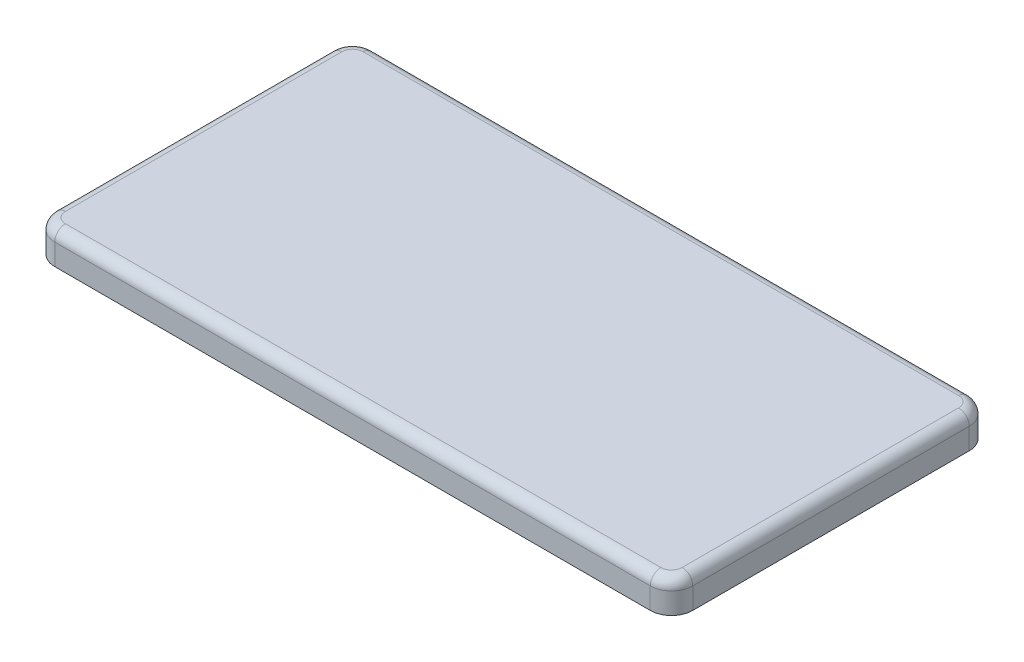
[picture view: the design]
ISO-10303-21;
HEADER;
FILE_DESCRIPTION(('STEP AP214'),'2;1');
FILE_NAME('part.step','',(''),(''),'','','');
FILE_SCHEMA(('AUTOMOTIVE_DESIGN { 1 0 10303 214 1 1 1 1 }'));
ENDSEC;
DATA;
#1=APPLICATION_CONTEXT('core data for automotive mechanical design processes');
#2=APPLICATION_PROTOCOL_DEFINITION('international standard','automotive_design',2000,#1);
#3=PRODUCT_CONTEXT('',#1,'mechanical');
#4=PRODUCT('Part','Part','',(#3));
#5=PRODUCT_RELATED_PRODUCT_CATEGORY('part','',(#4));
#6=PRODUCT_DEFINITION_FORMATION('','',#4);
#7=PRODUCT_DEFINITION_CONTEXT('part definition',#1,'design');
#8=PRODUCT_DEFINITION('design','',#6,#7);
#9=PRODUCT_DEFINITION_SHAPE('','',#8);
#10=(LENGTH_UNIT() NAMED_UNIT(*) SI_UNIT(.MILLI.,.METRE.));
#11=(NAMED_UNIT(*) PLANE_ANGLE_UNIT() SI_UNIT($,.RADIAN.));
#12=(NAMED_UNIT(*) SI_UNIT($,.STERADIAN.) SOLID_ANGLE_UNIT());
#13=UNCERTAINTY_MEASURE_WITH_UNIT(LENGTH_MEASURE(1.E-05),#10,'distance_accuracy_value','');
#14=(GEOMETRIC_REPRESENTATION_CONTEXT(3) GLOBAL_UNCERTAINTY_ASSIGNED_CONTEXT((#13)) GLOBAL_UNIT_ASSIGNED_CONTEXT((#10,
#11,#12)) REPRESENTATION_CONTEXT('',''));
#15=CARTESIAN_POINT('',(0.,0.,0.));
#16=DIRECTION('',(0.,0.,1.));
#17=DIRECTION('',(1.,0.,0.));
#18=AXIS2_PLACEMENT_3D('',#15,#16,#17);
#19=CARTESIAN_POINT('',(-28.,-0.5,13.));
#20=DIRECTION('',(0.,-1.,0.));
#21=DIRECTION('',(0.,0.,-1.));
#22=AXIS2_PLACEMENT_3D('',#19,#20,#21);
#23=PLANE('',#22);
#24=DIRECTION('',(1.,0.,0.));
#25=VECTOR('',#24,1.);
#26=CARTESIAN_POINT('',(-16.65,-0.5,-2.45));
#27=LINE('',#26,#25);
#28=CARTESIAN_POINT('',(-16.65,-0.5,-2.45));
#29=VERTEX_POINT('',#28);
#30=CARTESIAN_POINT('',(-13.35,-0.5,-2.45));
#31=VERTEX_POINT('',#30);
#32=EDGE_CURVE('E282',#29,#31,#27,.T.);
#33=ORIENTED_EDGE('',*,*,#32,.F.);
#34=DIRECTION('',(0.,0.,-1.));
#35=VECTOR('',#34,1.);
#36=CARTESIAN_POINT('',(-16.65,-0.5,2.45));
#37=LINE('',#36,#35);
#38=CARTESIAN_POINT('',(-16.65,-0.5,2.45));
#39=VERTEX_POINT('',#38);
#40=EDGE_CURVE('E256',#39,#29,#37,.T.);
#41=ORIENTED_EDGE('',*,*,#40,.F.);
#42=DIRECTION('',(-1.,0.,0.));
#43=VECTOR('',#42,1.);
#44=CARTESIAN_POINT('',(-16.65,-0.5,2.45));
#45=LINE('',#44,#43);
#46=CARTESIAN_POINT('',(-13.35,-0.5,2.45));
#47=VERTEX_POINT('',#46);
#48=EDGE_CURVE('E288',#47,#39,#45,.T.);
#49=ORIENTED_EDGE('',*,*,#48,.F.);
#50=DIRECTION('',(0.,0.,1.));
#51=VECTOR('',#50,1.);
#52=CARTESIAN_POINT('',(-13.35,-0.5,2.45));
#53=LINE('',#52,#51);
#54=EDGE_CURVE('E285',#31,#47,#53,.T.);
#55=ORIENTED_EDGE('',*,*,#54,.F.);
#56=EDGE_LOOP('',(#33,#41,#49,#55));
#57=FACE_BOUND('',#56,.T.);
#58=CARTESIAN_POINT('',(-28.,-0.5,13.));
#59=DIRECTION('',(0.,-1.,0.));
#60=DIRECTION('',(0.,0.,-1.));
#61=AXIS2_PLACEMENT_3D('',#58,#59,#60);
#62=CIRCLE('',#61,0.2);
#63=CARTESIAN_POINT('',(-28.,-0.5,13.2));
#64=VERTEX_POINT('',#63);
#65=CARTESIAN_POINT('',(-28.2,-0.5,13.));
#66=VERTEX_POINT('',#65);
#67=EDGE_CURVE('E300',#64,#66,#62,.T.);
#68=ORIENTED_EDGE('',*,*,#67,.T.);
#69=DIRECTION('',(0.,0.,-1.));
#70=VECTOR('',#69,1.);
#71=CARTESIAN_POINT('',(-28.2,-0.5,13.));
#72=LINE('',#71,#70);
#73=CARTESIAN_POINT('',(-28.2,-0.5,-13.));
#74=VERTEX_POINT('',#73);
#75=EDGE_CURVE('E303',#66,#74,#72,.T.);
#76=ORIENTED_EDGE('',*,*,#75,.T.);
#77=CARTESIAN_POINT('',(-28.,-0.5,-13.));
#78=DIRECTION('',(0.,-1.,0.));
#79=DIRECTION('',(0.,0.,-1.));
#80=AXIS2_PLACEMENT_3D('',#77,#78,#79);
#81=CIRCLE('',#80,0.2);
#82=CARTESIAN_POINT('',(-28.,-0.5,-13.2));
#83=VERTEX_POINT('',#82);
#84=EDGE_CURVE('E307',#74,#83,#81,.T.);
#85=ORIENTED_EDGE('',*,*,#84,.T.);
#86=DIRECTION('',(1.,0.,0.));
#87=VECTOR('',#86,1.);
#88=CARTESIAN_POINT('',(-28.,-0.5,-13.2));
#89=LINE('',#88,#87);
#90=CARTESIAN_POINT('',(28.,-0.5,-13.2));
#91=VERTEX_POINT('',#90);
#92=EDGE_CURVE('E310',#83,#91,#89,.T.);
#93=ORIENTED_EDGE('',*,*,#92,.T.);
#94=CARTESIAN_POINT('',(28.,-0.5,-13.));
#95=DIRECTION('',(0.,-1.,0.));
#96=DIRECTION('',(0.,0.,-1.));
#97=AXIS2_PLACEMENT_3D('',#94,#95,#96);
#98=CIRCLE('',#97,0.200000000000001);
#99=CARTESIAN_POINT('',(28.2,-0.5,-13.));
#100=VERTEX_POINT('',#99);
#101=EDGE_CURVE('E313',#91,#100,#98,.T.);
#102=ORIENTED_EDGE('',*,*,#101,.T.);
#103=DIRECTION('',(0.,0.,1.));
#104=VECTOR('',#103,1.);
#105=CARTESIAN_POINT('',(28.2,-0.5,13.));
#106=LINE('',#105,#104);
#107=CARTESIAN_POINT('',(28.2,-0.5,13.));
#108=VERTEX_POINT('',#107);
#109=EDGE_CURVE('E316',#100,#108,#106,.T.);
#110=ORIENTED_EDGE('',*,*,#109,.T.);
#111=CARTESIAN_POINT('',(28.,-0.5,13.));
#112=DIRECTION('',(0.,-1.,0.));
#113=DIRECTION('',(0.,0.,-1.));
#114=AXIS2_PLACEMENT_3D('',#111,#112,#113);
#115=CIRCLE('',#114,0.199999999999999);
#116=CARTESIAN_POINT('',(28.,-0.5,13.2));
#117=VERTEX_POINT('',#116);
#118=EDGE_CURVE('E319',#108,#117,#115,.T.);
#119=ORIENTED_EDGE('',*,*,#118,.T.);
#120=DIRECTION('',(-1.,0.,0.));
#121=VECTOR('',#120,1.);
#122=CARTESIAN_POINT('',(-28.,-0.5,13.2));
#123=LINE('',#122,#121);
#124=EDGE_CURVE('E322',#117,#64,#123,.T.);
#125=ORIENTED_EDGE('',*,*,#124,.T.);
#126=EDGE_LOOP('',(#68,#76,#85,#93,#102,#110,#119,#125));
#127=FACE_BOUND('',#126,.T.);
#128=DIRECTION('',(1.,0.,0.));
#129=VECTOR('',#128,1.);
#130=CARTESIAN_POINT('',(13.35,-0.5,-2.45));
#131=LINE('',#130,#129);
#132=CARTESIAN_POINT('',(13.35,-0.5,-2.45));
#133=VERTEX_POINT('',#132);
#134=CARTESIAN_POINT('',(16.65,-0.5,-2.45));
#135=VERTEX_POINT('',#134);
#136=EDGE_CURVE('E250',#133,#135,#131,.T.);
#137=ORIENTED_EDGE('',*,*,#136,.F.);
#138=DIRECTION('',(0.,0.,-1.));
#139=VECTOR('',#138,1.);
#140=CARTESIAN_POINT('',(13.35,-0.5,-2.45));
#141=LINE('',#140,#139);
#142=CARTESIAN_POINT('',(13.35,-0.5,2.45));
#143=VERTEX_POINT('',#142);
#144=EDGE_CURVE('E260',#143,#133,#141,.T.);
#145=ORIENTED_EDGE('',*,*,#144,.F.);
#146=DIRECTION('',(-1.,0.,0.));
#147=VECTOR('',#146,1.);
#148=CARTESIAN_POINT('',(13.35,-0.5,2.45));
#149=LINE('',#148,#147);
#150=CARTESIAN_POINT('',(16.65,-0.5,2.45));
#151=VERTEX_POINT('',#150);
#152=EDGE_CURVE('E272',#151,#143,#149,.T.);
#153=ORIENTED_EDGE('',*,*,#152,.F.);
#154=DIRECTION('',(0.,0.,1.));
#155=VECTOR('',#154,1.);
#156=CARTESIAN_POINT('',(16.65,-0.5,-2.45));
#157=LINE('',#156,#155);
#158=EDGE_CURVE('E270',#135,#151,#157,.T.);
#159=ORIENTED_EDGE('',*,*,#158,.F.);
#160=EDGE_LOOP('',(#137,#145,#153,#159));
#161=FACE_BOUND('',#160,.T.);
#162=ADVANCED_FACE('F35',(#57,#127,#161),#23,.T.);
#163=CARTESIAN_POINT('',(-28.,1.5,-13.));
#164=DIRECTION('',(0.,-1.,0.));
#165=DIRECTION('',(0.,0.,-1.));
#166=AXIS2_PLACEMENT_3D('',#163,#164,#165);
#167=CYLINDRICAL_SURFACE('',#166,2.);
#168=DIRECTION('',(0.,-1.,0.));
#169=VECTOR('',#168,1.);
#170=CARTESIAN_POINT('',(-30.,1.5,-13.));
#171=LINE('',#170,#169);
#172=CARTESIAN_POINT('',(-30.,0.5,-13.));
#173=VERTEX_POINT('',#172);
#174=CARTESIAN_POINT('',(-30.,-1.5,-13.));
#175=VERTEX_POINT('',#174);
#176=EDGE_CURVE('E403',#173,#175,#171,.T.);
#177=ORIENTED_EDGE('',*,*,#176,.F.);
#178=CARTESIAN_POINT('',(-28.,0.5,-13.));
#179=DIRECTION('',(0.,1.,0.));
#180=DIRECTION('',(0.,0.,1.));
#181=AXIS2_PLACEMENT_3D('',#178,#179,#180);
#182=CIRCLE('',#181,2.);
#183=CARTESIAN_POINT('',(-28.,0.5,-15.));
#184=VERTEX_POINT('',#183);
#185=EDGE_CURVE('E427',#173,#184,#182,.F.);
#186=ORIENTED_EDGE('',*,*,#185,.T.);
#187=DIRECTION('',(0.,-1.,0.));
#188=VECTOR('',#187,1.);
#189=CARTESIAN_POINT('',(-28.,1.5,-15.));
#190=LINE('',#189,#188);
#191=CARTESIAN_POINT('',(-28.,-1.5,-15.));
#192=VERTEX_POINT('',#191);
#193=EDGE_CURVE('E389',#184,#192,#190,.T.);
#194=ORIENTED_EDGE('',*,*,#193,.T.);
#195=CARTESIAN_POINT('',(-28.,-1.5,-13.));
#196=DIRECTION('',(0.,1.,0.));
#197=DIRECTION('',(0.,0.,1.));
#198=AXIS2_PLACEMENT_3D('',#195,#196,#197);
#199=CIRCLE('',#198,2.);
#200=EDGE_CURVE('E364',#192,#175,#199,.T.);
#201=ORIENTED_EDGE('',*,*,#200,.T.);
#202=EDGE_LOOP('',(#177,#186,#194,#201));
#203=FACE_BOUND('',#202,.T.);
#204=ADVANCED_FACE('F543',(#203),#167,.T.);
#205=CARTESIAN_POINT('',(-30.,1.5,13.));
#206=DIRECTION('',(1.,0.,0.));
#207=DIRECTION('',(0.,0.,-1.));
#208=AXIS2_PLACEMENT_3D('',#205,#206,#207);
#209=PLANE('',#208);
#210=DIRECTION('',(0.,-1.,0.));
#211=VECTOR('',#210,1.);
#212=CARTESIAN_POINT('',(-30.,1.5,13.));
#213=LINE('',#212,#211);
#214=CARTESIAN_POINT('',(-30.,0.5,13.));
#215=VERTEX_POINT('',#214);
#216=CARTESIAN_POINT('',(-30.,-1.5,13.));
#217=VERTEX_POINT('',#216);
#218=EDGE_CURVE('E401',#215,#217,#213,.T.);
#219=ORIENTED_EDGE('',*,*,#218,.F.);
#220=DIRECTION('',(0.,0.,1.));
#221=VECTOR('',#220,1.);
#222=CARTESIAN_POINT('',(-30.,0.5,-13.));
#223=LINE('',#222,#221);
#224=EDGE_CURVE('E425',#215,#173,#223,.F.);
#225=ORIENTED_EDGE('',*,*,#224,.T.);
#226=ORIENTED_EDGE('',*,*,#176,.T.);
#227=DIRECTION('',(0.,0.,1.));
#228=VECTOR('',#227,1.);
#229=CARTESIAN_POINT('',(-30.,-1.5,13.));
#230=LINE('',#229,#228);
#231=EDGE_CURVE('E367',#175,#217,#230,.T.);
#232=ORIENTED_EDGE('',*,*,#231,.T.);
#233=EDGE_LOOP('',(#219,#225,#226,#232));
#234=FACE_BOUND('',#233,.T.);
#235=ADVANCED_FACE('F549',(#234),#209,.F.);
#236=CARTESIAN_POINT('',(-28.,1.5,13.));
#237=DIRECTION('',(0.,-1.,0.));
#238=DIRECTION('',(0.,0.,-1.));
#239=AXIS2_PLACEMENT_3D('',#236,#237,#238);
#240=CYLINDRICAL_SURFACE('',#239,2.);
#241=DIRECTION('',(0.,-1.,0.));
#242=VECTOR('',#241,1.);
#243=CARTESIAN_POINT('',(-28.,1.5,15.));
#244=LINE('',#243,#242);
#245=CARTESIAN_POINT('',(-28.,0.5,15.));
#246=VERTEX_POINT('',#245);
#247=CARTESIAN_POINT('',(-28.,-1.5,15.));
#248=VERTEX_POINT('',#247);
#249=EDGE_CURVE('E399',#246,#248,#244,.T.);
#250=ORIENTED_EDGE('',*,*,#249,.F.);
#251=CARTESIAN_POINT('',(-28.,0.5,13.));
#252=DIRECTION('',(0.,1.,0.));
#253=DIRECTION('',(0.,0.,1.));
#254=AXIS2_PLACEMENT_3D('',#251,#252,#253);
#255=CIRCLE('',#254,2.);
#256=EDGE_CURVE('E422',#246,#215,#255,.F.);
#257=ORIENTED_EDGE('',*,*,#256,.T.);
#258=ORIENTED_EDGE('',*,*,#218,.T.);
#259=CARTESIAN_POINT('',(-28.,-1.5,13.));
#260=DIRECTION('',(0.,1.,0.));
#261=DIRECTION('',(0.,0.,1.));
#262=AXIS2_PLACEMENT_3D('',#259,#260,#261);
#263=CIRCLE('',#262,2.);
#264=EDGE_CURVE('E371',#217,#248,#263,.T.);
#265=ORIENTED_EDGE('',*,*,#264,.T.);
#266=EDGE_LOOP('',(#250,#257,#258,#265));
#267=FACE_BOUND('',#266,.T.);
#268=ADVANCED_FACE('F619',(#267),#240,.T.);
#269=CARTESIAN_POINT('',(-28.,1.5,15.));
#270=DIRECTION('',(0.,0.,-1.));
#271=DIRECTION('',(-1.,0.,0.));
#272=AXIS2_PLACEMENT_3D('',#269,#270,#271);
#273=PLANE('',#272);
#274=DIRECTION('',(0.,-1.,0.));
#275=VECTOR('',#274,1.);
#276=CARTESIAN_POINT('',(28.,1.5,15.));
#277=LINE('',#276,#275);
#278=CARTESIAN_POINT('',(28.,0.5,15.));
#279=VERTEX_POINT('',#278);
#280=CARTESIAN_POINT('',(28.,-1.5,15.));
#281=VERTEX_POINT('',#280);
#282=EDGE_CURVE('E397',#279,#281,#277,.T.);
#283=ORIENTED_EDGE('',*,*,#282,.F.);
#284=DIRECTION('',(1.,0.,0.));
#285=VECTOR('',#284,1.);
#286=CARTESIAN_POINT('',(-28.,0.5,15.));
#287=LINE('',#286,#285);
#288=EDGE_CURVE('E437',#279,#246,#287,.F.);
#289=ORIENTED_EDGE('',*,*,#288,.T.);
#290=ORIENTED_EDGE('',*,*,#249,.T.);
#291=DIRECTION('',(1.,0.,0.));
#292=VECTOR('',#291,1.);
#293=CARTESIAN_POINT('',(-28.,-1.5,15.));
#294=LINE('',#293,#292);
#295=EDGE_CURVE('E374',#248,#281,#294,.T.);
#296=ORIENTED_EDGE('',*,*,#295,.T.);
#297=EDGE_LOOP('',(#283,#289,#290,#296));
#298=FACE_BOUND('',#297,.T.);
#299=ADVANCED_FACE('F615',(#298),#273,.F.);
#300=CARTESIAN_POINT('',(28.,1.5,13.));
#301=DIRECTION('',(0.,-1.,0.));
#302=DIRECTION('',(0.,0.,-1.));
#303=AXIS2_PLACEMENT_3D('',#300,#301,#302);
#304=CYLINDRICAL_SURFACE('',#303,2.);
#305=DIRECTION('',(0.,-1.,0.));
#306=VECTOR('',#305,1.);
#307=CARTESIAN_POINT('',(30.,1.5,13.));
#308=LINE('',#307,#306);
#309=CARTESIAN_POINT('',(30.,0.5,13.));
#310=VERTEX_POINT('',#309);
#311=CARTESIAN_POINT('',(30.,-1.5,13.));
#312=VERTEX_POINT('',#311);
#313=EDGE_CURVE('E395',#310,#312,#308,.T.);
#314=ORIENTED_EDGE('',*,*,#313,.F.);
#315=CARTESIAN_POINT('',(28.,0.5,13.));
#316=DIRECTION('',(0.,1.,0.));
#317=DIRECTION('',(0.,0.,1.));
#318=AXIS2_PLACEMENT_3D('',#315,#316,#317);
#319=CIRCLE('',#318,2.);
#320=EDGE_CURVE('E435',#310,#279,#319,.F.);
#321=ORIENTED_EDGE('',*,*,#320,.T.);
#322=ORIENTED_EDGE('',*,*,#282,.T.);
#323=CARTESIAN_POINT('',(28.,-1.5,13.));
#324=DIRECTION('',(0.,1.,0.));
#325=DIRECTION('',(0.,0.,1.));
#326=AXIS2_PLACEMENT_3D('',#323,#324,#325);
#327=CIRCLE('',#326,2.);
#328=EDGE_CURVE('E377',#281,#312,#327,.T.);
#329=ORIENTED_EDGE('',*,*,#328,.T.);
#330=EDGE_LOOP('',(#314,#321,#322,#329));
#331=FACE_BOUND('',#330,.T.);
#332=ADVANCED_FACE('F611',(#331),#304,.T.);
#333=CARTESIAN_POINT('',(30.,1.5,13.));
#334=DIRECTION('',(-1.,0.,0.));
#335=DIRECTION('',(0.,0.,1.));
#336=AXIS2_PLACEMENT_3D('',#333,#334,#335);
#337=PLANE('',#336);
#338=DIRECTION('',(0.,-1.,0.));
#339=VECTOR('',#338,1.);
#340=CARTESIAN_POINT('',(30.,1.5,-13.));
#341=LINE('',#340,#339);
#342=CARTESIAN_POINT('',(30.,0.5,-13.));
#343=VERTEX_POINT('',#342);
#344=CARTESIAN_POINT('',(30.,-1.5,-13.));
#345=VERTEX_POINT('',#344);
#346=EDGE_CURVE('E393',#343,#345,#341,.T.);
#347=ORIENTED_EDGE('',*,*,#346,.F.);
#348=DIRECTION('',(0.,0.,-1.));
#349=VECTOR('',#348,1.);
#350=CARTESIAN_POINT('',(30.,0.5,13.));
#351=LINE('',#350,#349);
#352=EDGE_CURVE('E433',#343,#310,#351,.F.);
#353=ORIENTED_EDGE('',*,*,#352,.T.);
#354=ORIENTED_EDGE('',*,*,#313,.T.);
#355=DIRECTION('',(0.,0.,-1.));
#356=VECTOR('',#355,1.);
#357=CARTESIAN_POINT('',(30.,-1.5,13.));
#358=LINE('',#357,#356);
#359=EDGE_CURVE('E380',#312,#345,#358,.T.);
#360=ORIENTED_EDGE('',*,*,#359,.T.);
#361=EDGE_LOOP('',(#347,#353,#354,#360));
#362=FACE_BOUND('',#361,.T.);
#363=ADVANCED_FACE('F607',(#362),#337,.F.);
#364=CARTESIAN_POINT('',(28.,1.5,-13.));
#365=DIRECTION('',(0.,-1.,0.));
#366=DIRECTION('',(0.,0.,-1.));
#367=AXIS2_PLACEMENT_3D('',#364,#365,#366);
#368=CYLINDRICAL_SURFACE('',#367,2.);
#369=DIRECTION('',(0.,-1.,0.));
#370=VECTOR('',#369,1.);
#371=CARTESIAN_POINT('',(28.,1.5,-15.));
#372=LINE('',#371,#370);
#373=CARTESIAN_POINT('',(28.,0.5,-15.));
#374=VERTEX_POINT('',#373);
#375=CARTESIAN_POINT('',(28.,-1.5,-15.));
#376=VERTEX_POINT('',#375);
#377=EDGE_CURVE('E391',#374,#376,#372,.T.);
#378=ORIENTED_EDGE('',*,*,#377,.F.);
#379=CARTESIAN_POINT('',(28.,0.5,-13.));
#380=DIRECTION('',(0.,1.,0.));
#381=DIRECTION('',(0.,0.,1.));
#382=AXIS2_PLACEMENT_3D('',#379,#380,#381);
#383=CIRCLE('',#382,2.);
#384=EDGE_CURVE('E431',#374,#343,#383,.F.);
#385=ORIENTED_EDGE('',*,*,#384,.T.);
#386=ORIENTED_EDGE('',*,*,#346,.T.);
#387=CARTESIAN_POINT('',(28.,-1.5,-13.));
#388=DIRECTION('',(0.,1.,0.));
#389=DIRECTION('',(0.,0.,1.));
#390=AXIS2_PLACEMENT_3D('',#387,#388,#389);
#391=CIRCLE('',#390,2.);
#392=EDGE_CURVE('E383',#345,#376,#391,.T.);
#393=ORIENTED_EDGE('',*,*,#392,.T.);
#394=EDGE_LOOP('',(#378,#385,#386,#393));
#395=FACE_BOUND('',#394,.T.);
#396=ADVANCED_FACE('F603',(#395),#368,.T.);
#397=CARTESIAN_POINT('',(-28.,1.5,-15.));
#398=DIRECTION('',(0.,0.,1.));
#399=DIRECTION('',(1.,0.,0.));
#400=AXIS2_PLACEMENT_3D('',#397,#398,#399);
#401=PLANE('',#400);
#402=ORIENTED_EDGE('',*,*,#193,.F.);
#403=DIRECTION('',(-1.,0.,0.));
#404=VECTOR('',#403,1.);
#405=CARTESIAN_POINT('',(28.,0.5,-15.));
#406=LINE('',#405,#404);
#407=EDGE_CURVE('E429',#184,#374,#406,.F.);
#408=ORIENTED_EDGE('',*,*,#407,.T.);
#409=ORIENTED_EDGE('',*,*,#377,.T.);
#410=DIRECTION('',(-1.,0.,0.));
#411=VECTOR('',#410,1.);
#412=CARTESIAN_POINT('',(-28.,-1.5,-15.));
#413=LINE('',#412,#411);
#414=EDGE_CURVE('E386',#376,#192,#413,.T.);
#415=ORIENTED_EDGE('',*,*,#414,.T.);
#416=EDGE_LOOP('',(#402,#408,#409,#415));
#417=FACE_BOUND('',#416,.T.);
#418=ADVANCED_FACE('F595',(#417),#401,.F.);
#419=CARTESIAN_POINT('',(-28.,1.5,-13.));
#420=DIRECTION('',(0.,1.,0.));
#421=DIRECTION('',(0.,0.,1.));
#422=AXIS2_PLACEMENT_3D('',#419,#420,#421);
#423=PLANE('',#422);
#424=DIRECTION('',(0.,0.,1.));
#425=VECTOR('',#424,1.);
#426=CARTESIAN_POINT('',(-29.,1.5,13.));
#427=LINE('',#426,#425);
#428=CARTESIAN_POINT('',(-29.,1.5,-13.));
#429=VERTEX_POINT('',#428);
#430=CARTESIAN_POINT('',(-29.,1.5,13.));
#431=VERTEX_POINT('',#430);
#432=EDGE_CURVE('E417',#429,#431,#427,.T.);
#433=ORIENTED_EDGE('',*,*,#432,.T.);
#434=CARTESIAN_POINT('',(-28.,1.5,13.));
#435=DIRECTION('',(0.,1.,0.));
#436=DIRECTION('',(0.,0.,1.));
#437=AXIS2_PLACEMENT_3D('',#434,#435,#436);
#438=CIRCLE('',#437,1.);
#439=CARTESIAN_POINT('',(-28.,1.5,14.));
#440=VERTEX_POINT('',#439);
#441=EDGE_CURVE('E419',#431,#440,#438,.T.);
#442=ORIENTED_EDGE('',*,*,#441,.T.);
#443=DIRECTION('',(1.,0.,0.));
#444=VECTOR('',#443,1.);
#445=CARTESIAN_POINT('',(28.,1.5,14.));
#446=LINE('',#445,#444);
#447=CARTESIAN_POINT('',(28.,1.5,14.));
#448=VERTEX_POINT('',#447);
#449=EDGE_CURVE('E405',#440,#448,#446,.T.);
#450=ORIENTED_EDGE('',*,*,#449,.T.);
#451=CARTESIAN_POINT('',(28.,1.5,13.));
#452=DIRECTION('',(0.,1.,0.));
#453=DIRECTION('',(0.,0.,1.));
#454=AXIS2_PLACEMENT_3D('',#451,#452,#453);
#455=CIRCLE('',#454,1.);
#456=CARTESIAN_POINT('',(29.,1.5,13.));
#457=VERTEX_POINT('',#456);
#458=EDGE_CURVE('E407',#448,#457,#455,.T.);
#459=ORIENTED_EDGE('',*,*,#458,.T.);
#460=DIRECTION('',(0.,0.,-1.));
#461=VECTOR('',#460,1.);
#462=CARTESIAN_POINT('',(29.,1.5,-13.));
#463=LINE('',#462,#461);
#464=CARTESIAN_POINT('',(29.,1.5,-13.));
#465=VERTEX_POINT('',#464);
#466=EDGE_CURVE('E409',#457,#465,#463,.T.);
#467=ORIENTED_EDGE('',*,*,#466,.T.);
#468=CARTESIAN_POINT('',(28.,1.5,-13.));
#469=DIRECTION('',(0.,1.,0.));
#470=DIRECTION('',(0.,0.,1.));
#471=AXIS2_PLACEMENT_3D('',#468,#469,#470);
#472=CIRCLE('',#471,1.);
#473=CARTESIAN_POINT('',(28.,1.5,-14.));
#474=VERTEX_POINT('',#473);
#475=EDGE_CURVE('E411',#465,#474,#472,.T.);
#476=ORIENTED_EDGE('',*,*,#475,.T.);
#477=DIRECTION('',(-1.,0.,0.));
#478=VECTOR('',#477,1.);
#479=CARTESIAN_POINT('',(-28.,1.5,-14.));
#480=LINE('',#479,#478);
#481=CARTESIAN_POINT('',(-28.,1.5,-14.));
#482=VERTEX_POINT('',#481);
#483=EDGE_CURVE('E413',#474,#482,#480,.T.);
#484=ORIENTED_EDGE('',*,*,#483,.T.);
#485=CARTESIAN_POINT('',(-28.,1.5,-13.));
#486=DIRECTION('',(0.,1.,0.));
#487=DIRECTION('',(0.,0.,1.));
#488=AXIS2_PLACEMENT_3D('',#485,#486,#487);
#489=CIRCLE('',#488,1.);
#490=EDGE_CURVE('E415',#482,#429,#489,.T.);
#491=ORIENTED_EDGE('',*,*,#490,.T.);
#492=EDGE_LOOP('',(#433,#442,#450,#459,#467,#476,#484,#491));
#493=FACE_BOUND('',#492,.T.);
#494=ADVANCED_FACE('F591',(#493),#423,.T.);
#495=CARTESIAN_POINT('',(-28.,-1.5,-13.));
#496=DIRECTION('',(0.,1.,0.));
#497=DIRECTION('',(0.,0.,1.));
#498=AXIS2_PLACEMENT_3D('',#495,#496,#497);
#499=PLANE('',#498);
#500=DIRECTION('',(0.,0.,-1.));
#501=VECTOR('',#500,1.);
#502=CARTESIAN_POINT('',(-28.2,-1.5,13.));
#503=LINE('',#502,#501);
#504=CARTESIAN_POINT('',(-28.2,-1.5,13.));
#505=VERTEX_POINT('',#504);
#506=CARTESIAN_POINT('',(-28.2,-1.5,-13.));
#507=VERTEX_POINT('',#506);
#508=EDGE_CURVE('E327',#505,#507,#503,.T.);
#509=ORIENTED_EDGE('',*,*,#508,.F.);
#510=CARTESIAN_POINT('',(-28.,-1.5,13.));
#511=DIRECTION('',(0.,-1.,0.));
#512=DIRECTION('',(0.,0.,-1.));
#513=AXIS2_PLACEMENT_3D('',#510,#511,#512);
#514=CIRCLE('',#513,0.2);
#515=CARTESIAN_POINT('',(-28.,-1.5,13.2));
#516=VERTEX_POINT('',#515);
#517=EDGE_CURVE('E294',#516,#505,#514,.T.);
#518=ORIENTED_EDGE('',*,*,#517,.F.);
#519=DIRECTION('',(-1.,0.,0.));
#520=VECTOR('',#519,1.);
#521=CARTESIAN_POINT('',(-28.,-1.5,13.2));
#522=LINE('',#521,#520);
#523=CARTESIAN_POINT('',(28.,-1.5,13.2));
#524=VERTEX_POINT('',#523);
#525=EDGE_CURVE('E304',#524,#516,#522,.T.);
#526=ORIENTED_EDGE('',*,*,#525,.F.);
#527=CARTESIAN_POINT('',(28.,-1.5,13.));
#528=DIRECTION('',(0.,-1.,0.));
#529=DIRECTION('',(0.,0.,-1.));
#530=AXIS2_PLACEMENT_3D('',#527,#528,#529);
#531=CIRCLE('',#530,0.199999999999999);
#532=CARTESIAN_POINT('',(28.2,-1.5,13.));
#533=VERTEX_POINT('',#532);
#534=EDGE_CURVE('E342',#533,#524,#531,.T.);
#535=ORIENTED_EDGE('',*,*,#534,.F.);
#536=DIRECTION('',(0.,0.,1.));
#537=VECTOR('',#536,1.);
#538=CARTESIAN_POINT('',(28.2,-1.5,13.));
#539=LINE('',#538,#537);
#540=CARTESIAN_POINT('',(28.2,-1.5,-13.));
#541=VERTEX_POINT('',#540);
#542=EDGE_CURVE('E339',#541,#533,#539,.T.);
#543=ORIENTED_EDGE('',*,*,#542,.F.);
#544=CARTESIAN_POINT('',(28.,-1.5,-13.));
#545=DIRECTION('',(0.,-1.,0.));
#546=DIRECTION('',(0.,0.,-1.));
#547=AXIS2_PLACEMENT_3D('',#544,#545,#546);
#548=CIRCLE('',#547,0.200000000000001);
#549=CARTESIAN_POINT('',(28.,-1.5,-13.2));
#550=VERTEX_POINT('',#549);
#551=EDGE_CURVE('E336',#550,#541,#548,.T.);
#552=ORIENTED_EDGE('',*,*,#551,.F.);
#553=DIRECTION('',(1.,0.,0.));
#554=VECTOR('',#553,1.);
#555=CARTESIAN_POINT('',(-28.,-1.5,-13.2));
#556=LINE('',#555,#554);
#557=CARTESIAN_POINT('',(-28.,-1.5,-13.2));
#558=VERTEX_POINT('',#557);
#559=EDGE_CURVE('E333',#558,#550,#556,.T.);
#560=ORIENTED_EDGE('',*,*,#559,.F.);
#561=CARTESIAN_POINT('',(-28.,-1.5,-13.));
#562=DIRECTION('',(0.,-1.,0.));
#563=DIRECTION('',(0.,0.,-1.));
#564=AXIS2_PLACEMENT_3D('',#561,#562,#563);
#565=CIRCLE('',#564,0.2);
#566=EDGE_CURVE('E330',#507,#558,#565,.T.);
#567=ORIENTED_EDGE('',*,*,#566,.F.);
#568=EDGE_LOOP('',(#509,#518,#526,#535,#543,#552,#560,#567));
#569=FACE_BOUND('',#568,.T.);
#570=ORIENTED_EDGE('',*,*,#200,.F.);
#571=ORIENTED_EDGE('',*,*,#414,.F.);
#572=ORIENTED_EDGE('',*,*,#392,.F.);
#573=ORIENTED_EDGE('',*,*,#359,.F.);
#574=ORIENTED_EDGE('',*,*,#328,.F.);
#575=ORIENTED_EDGE('',*,*,#295,.F.);
#576=ORIENTED_EDGE('',*,*,#264,.F.);
#577=ORIENTED_EDGE('',*,*,#231,.F.);
#578=EDGE_LOOP('',(#570,#571,#572,#573,#574,#575,#576,#577));
#579=FACE_BOUND('',#578,.T.);
#580=ADVANCED_FACE('F594',(#569,#579),#499,.F.);
#581=CARTESIAN_POINT('',(28.,0.5,-13.));
#582=DIRECTION('',(0.,1.,0.));
#583=DIRECTION('',(0.,0.,1.));
#584=AXIS2_PLACEMENT_3D('',#581,#582,#583);
#585=TOROIDAL_SURFACE('',#584,1.,1.);
#586=CARTESIAN_POINT('',(29.,0.5,-13.));
#587=DIRECTION('',(0.,0.,1.));
#588=DIRECTION('',(1.,0.,0.));
#589=AXIS2_PLACEMENT_3D('',#586,#587,#588);
#590=CIRCLE('',#589,1.);
#591=EDGE_CURVE('E455',#343,#465,#590,.T.);
#592=ORIENTED_EDGE('',*,*,#591,.F.);
#593=ORIENTED_EDGE('',*,*,#384,.F.);
#594=CARTESIAN_POINT('',(28.,0.5,-14.));
#595=DIRECTION('',(-1.,0.,0.));
#596=DIRECTION('',(0.,0.,1.));
#597=AXIS2_PLACEMENT_3D('',#594,#595,#596);
#598=CIRCLE('',#597,1.);
#599=EDGE_CURVE('E368',#474,#374,#598,.T.);
#600=ORIENTED_EDGE('',*,*,#599,.F.);
#601=ORIENTED_EDGE('',*,*,#475,.F.);
#602=EDGE_LOOP('',(#592,#593,#600,#601));
#603=FACE_BOUND('',#602,.T.);
#604=ADVANCED_FACE('F599',(#603),#585,.T.);
#605=CARTESIAN_POINT('',(-28.,0.5,-14.));
#606=DIRECTION('',(1.,0.,0.));
#607=DIRECTION('',(0.,0.,-1.));
#608=AXIS2_PLACEMENT_3D('',#605,#606,#607);
#609=CYLINDRICAL_SURFACE('',#608,1.);
#610=ORIENTED_EDGE('',*,*,#599,.T.);
#611=ORIENTED_EDGE('',*,*,#407,.F.);
#612=CARTESIAN_POINT('',(-28.,0.5,-14.));
#613=DIRECTION('',(-1.,0.,0.));
#614=DIRECTION('',(0.,0.,1.));
#615=AXIS2_PLACEMENT_3D('',#612,#613,#614);
#616=CIRCLE('',#615,1.);
#617=EDGE_CURVE('E452',#482,#184,#616,.T.);
#618=ORIENTED_EDGE('',*,*,#617,.F.);
#619=ORIENTED_EDGE('',*,*,#483,.F.);
#620=EDGE_LOOP('',(#610,#611,#618,#619));
#621=FACE_BOUND('',#620,.T.);
#622=ADVANCED_FACE('F649',(#621),#609,.T.);
#623=CARTESIAN_POINT('',(29.,0.5,-13.));
#624=DIRECTION('',(0.,0.,1.));
#625=DIRECTION('',(1.,0.,0.));
#626=AXIS2_PLACEMENT_3D('',#623,#624,#625);
#627=CYLINDRICAL_SURFACE('',#626,1.);
#628=ORIENTED_EDGE('',*,*,#591,.T.);
#629=ORIENTED_EDGE('',*,*,#466,.F.);
#630=CARTESIAN_POINT('',(29.,0.5,13.));
#631=DIRECTION('',(0.,0.,1.));
#632=DIRECTION('',(1.,0.,0.));
#633=AXIS2_PLACEMENT_3D('',#630,#631,#632);
#634=CIRCLE('',#633,1.);
#635=EDGE_CURVE('E449',#310,#457,#634,.T.);
#636=ORIENTED_EDGE('',*,*,#635,.F.);
#637=ORIENTED_EDGE('',*,*,#352,.F.);
#638=EDGE_LOOP('',(#628,#629,#636,#637));
#639=FACE_BOUND('',#638,.T.);
#640=ADVANCED_FACE('F645',(#639),#627,.T.);
#641=CARTESIAN_POINT('',(-28.,0.5,-13.));
#642=DIRECTION('',(0.,1.,0.));
#643=DIRECTION('',(0.,0.,1.));
#644=AXIS2_PLACEMENT_3D('',#641,#642,#643);
#645=TOROIDAL_SURFACE('',#644,1.,1.);
#646=ORIENTED_EDGE('',*,*,#617,.T.);
#647=ORIENTED_EDGE('',*,*,#185,.F.);
#648=CARTESIAN_POINT('',(-29.,0.5,-13.));
#649=DIRECTION('',(0.,0.,1.));
#650=DIRECTION('',(1.,0.,0.));
#651=AXIS2_PLACEMENT_3D('',#648,#649,#650);
#652=CIRCLE('',#651,1.);
#653=EDGE_CURVE('E446',#429,#173,#652,.T.);
#654=ORIENTED_EDGE('',*,*,#653,.F.);
#655=ORIENTED_EDGE('',*,*,#490,.F.);
#656=EDGE_LOOP('',(#646,#647,#654,#655));
#657=FACE_BOUND('',#656,.T.);
#658=ADVANCED_FACE('F641',(#657),#645,.T.);
#659=CARTESIAN_POINT('',(28.,0.5,13.));
#660=DIRECTION('',(0.,1.,0.));
#661=DIRECTION('',(0.,0.,1.));
#662=AXIS2_PLACEMENT_3D('',#659,#660,#661);
#663=TOROIDAL_SURFACE('',#662,1.,1.);
#664=ORIENTED_EDGE('',*,*,#635,.T.);
#665=ORIENTED_EDGE('',*,*,#458,.F.);
#666=CARTESIAN_POINT('',(28.,0.5,14.));
#667=DIRECTION('',(-1.,0.,0.));
#668=DIRECTION('',(0.,0.,1.));
#669=AXIS2_PLACEMENT_3D('',#666,#667,#668);
#670=CIRCLE('',#669,1.);
#671=EDGE_CURVE('E443',#279,#448,#670,.T.);
#672=ORIENTED_EDGE('',*,*,#671,.F.);
#673=ORIENTED_EDGE('',*,*,#320,.F.);
#674=EDGE_LOOP('',(#664,#665,#672,#673));
#675=FACE_BOUND('',#674,.T.);
#676=ADVANCED_FACE('F637',(#675),#663,.T.);
#677=CARTESIAN_POINT('',(-29.,0.5,-13.));
#678=DIRECTION('',(0.,0.,-1.));
#679=DIRECTION('',(-1.,0.,0.));
#680=AXIS2_PLACEMENT_3D('',#677,#678,#679);
#681=CYLINDRICAL_SURFACE('',#680,1.);
#682=ORIENTED_EDGE('',*,*,#653,.T.);
#683=ORIENTED_EDGE('',*,*,#224,.F.);
#684=CARTESIAN_POINT('',(-29.,0.5,13.));
#685=DIRECTION('',(0.,0.,1.));
#686=DIRECTION('',(1.,0.,0.));
#687=AXIS2_PLACEMENT_3D('',#684,#685,#686);
#688=CIRCLE('',#687,1.);
#689=EDGE_CURVE('E441',#431,#215,#688,.T.);
#690=ORIENTED_EDGE('',*,*,#689,.F.);
#691=ORIENTED_EDGE('',*,*,#432,.F.);
#692=EDGE_LOOP('',(#682,#683,#690,#691));
#693=FACE_BOUND('',#692,.T.);
#694=ADVANCED_FACE('F633',(#693),#681,.T.);
#695=CARTESIAN_POINT('',(-28.,0.5,14.));
#696=DIRECTION('',(-1.,0.,0.));
#697=DIRECTION('',(0.,0.,1.));
#698=AXIS2_PLACEMENT_3D('',#695,#696,#697);
#699=CYLINDRICAL_SURFACE('',#698,1.);
#700=ORIENTED_EDGE('',*,*,#671,.T.);
#701=ORIENTED_EDGE('',*,*,#449,.F.);
#702=CARTESIAN_POINT('',(-28.,0.5,14.));
#703=DIRECTION('',(-1.,0.,0.));
#704=DIRECTION('',(0.,0.,1.));
#705=AXIS2_PLACEMENT_3D('',#702,#703,#704);
#706=CIRCLE('',#705,1.);
#707=EDGE_CURVE('E349',#246,#440,#706,.T.);
#708=ORIENTED_EDGE('',*,*,#707,.F.);
#709=ORIENTED_EDGE('',*,*,#288,.F.);
#710=EDGE_LOOP('',(#700,#701,#708,#709));
#711=FACE_BOUND('',#710,.T.);
#712=ADVANCED_FACE('F629',(#711),#699,.T.);
#713=CARTESIAN_POINT('',(-28.,0.5,13.));
#714=DIRECTION('',(0.,1.,0.));
#715=DIRECTION('',(0.,0.,1.));
#716=AXIS2_PLACEMENT_3D('',#713,#714,#715);
#717=TOROIDAL_SURFACE('',#716,1.,1.);
#718=ORIENTED_EDGE('',*,*,#689,.T.);
#719=ORIENTED_EDGE('',*,*,#256,.F.);
#720=ORIENTED_EDGE('',*,*,#707,.T.);
#721=ORIENTED_EDGE('',*,*,#441,.F.);
#722=EDGE_LOOP('',(#718,#719,#720,#721));
#723=FACE_BOUND('',#722,.T.);
#724=ADVANCED_FACE('F589',(#723),#717,.T.);
#725=CARTESIAN_POINT('',(-28.,-0.5,13.));
#726=DIRECTION('',(0.,-1.,0.));
#727=DIRECTION('',(0.,0.,-1.));
#728=AXIS2_PLACEMENT_3D('',#725,#726,#727);
#729=CYLINDRICAL_SURFACE('',#728,0.2);
#730=ORIENTED_EDGE('',*,*,#517,.T.);
#731=DIRECTION('',(0.,-1.,0.));
#732=VECTOR('',#731,1.);
#733=CARTESIAN_POINT('',(-28.2,-0.5,13.));
#734=LINE('',#733,#732);
#735=EDGE_CURVE('E325',#66,#505,#734,.T.);
#736=ORIENTED_EDGE('',*,*,#735,.F.);
#737=ORIENTED_EDGE('',*,*,#67,.F.);
#738=DIRECTION('',(0.,-1.,0.));
#739=VECTOR('',#738,1.);
#740=CARTESIAN_POINT('',(-28.,-0.5,13.2));
#741=LINE('',#740,#739);
#742=EDGE_CURVE('E347',#64,#516,#741,.T.);
#743=ORIENTED_EDGE('',*,*,#742,.T.);
#744=EDGE_LOOP('',(#730,#736,#737,#743));
#745=FACE_BOUND('',#744,.T.);
#746=ADVANCED_FACE('F562',(#745),#729,.F.);
#747=CARTESIAN_POINT('',(-28.,-0.5,13.2));
#748=DIRECTION('',(0.,0.,1.));
#749=DIRECTION('',(1.,0.,0.));
#750=AXIS2_PLACEMENT_3D('',#747,#748,#749);
#751=PLANE('',#750);
#752=ORIENTED_EDGE('',*,*,#525,.T.);
#753=ORIENTED_EDGE('',*,*,#742,.F.);
#754=ORIENTED_EDGE('',*,*,#124,.F.);
#755=DIRECTION('',(0.,-1.,0.));
#756=VECTOR('',#755,1.);
#757=CARTESIAN_POINT('',(28.,-0.5,13.2));
#758=LINE('',#757,#756);
#759=EDGE_CURVE('E350',#117,#524,#758,.T.);
#760=ORIENTED_EDGE('',*,*,#759,.T.);
#761=EDGE_LOOP('',(#752,#753,#754,#760));
#762=FACE_BOUND('',#761,.T.);
#763=ADVANCED_FACE('F558',(#762),#751,.F.);
#764=CARTESIAN_POINT('',(28.,-0.5,13.));
#765=DIRECTION('',(0.,-1.,0.));
#766=DIRECTION('',(0.,0.,-1.));
#767=AXIS2_PLACEMENT_3D('',#764,#765,#766);
#768=CYLINDRICAL_SURFACE('',#767,0.199999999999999);
#769=ORIENTED_EDGE('',*,*,#534,.T.);
#770=ORIENTED_EDGE('',*,*,#759,.F.);
#771=ORIENTED_EDGE('',*,*,#118,.F.);
#772=DIRECTION('',(0.,-1.,0.));
#773=VECTOR('',#772,1.);
#774=CARTESIAN_POINT('',(28.2,-0.5,13.));
#775=LINE('',#774,#773);
#776=EDGE_CURVE('E352',#108,#533,#775,.T.);
#777=ORIENTED_EDGE('',*,*,#776,.T.);
#778=EDGE_LOOP('',(#769,#770,#771,#777));
#779=FACE_BOUND('',#778,.T.);
#780=ADVANCED_FACE('F561',(#779),#768,.F.);
#781=CARTESIAN_POINT('',(28.2,-0.5,13.));
#782=DIRECTION('',(1.,0.,0.));
#783=DIRECTION('',(0.,0.,-1.));
#784=AXIS2_PLACEMENT_3D('',#781,#782,#783);
#785=PLANE('',#784);
#786=ORIENTED_EDGE('',*,*,#542,.T.);
#787=ORIENTED_EDGE('',*,*,#776,.F.);
#788=ORIENTED_EDGE('',*,*,#109,.F.);
#789=DIRECTION('',(0.,-1.,0.));
#790=VECTOR('',#789,1.);
#791=CARTESIAN_POINT('',(28.2,-0.5,-13.));
#792=LINE('',#791,#790);
#793=EDGE_CURVE('E354',#100,#541,#792,.T.);
#794=ORIENTED_EDGE('',*,*,#793,.T.);
#795=EDGE_LOOP('',(#786,#787,#788,#794));
#796=FACE_BOUND('',#795,.T.);
#797=ADVANCED_FACE('F566',(#796),#785,.F.);
#798=CARTESIAN_POINT('',(28.,-0.5,-13.));
#799=DIRECTION('',(0.,-1.,0.));
#800=DIRECTION('',(0.,0.,-1.));
#801=AXIS2_PLACEMENT_3D('',#798,#799,#800);
#802=CYLINDRICAL_SURFACE('',#801,0.200000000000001);
#803=ORIENTED_EDGE('',*,*,#551,.T.);
#804=ORIENTED_EDGE('',*,*,#793,.F.);
#805=ORIENTED_EDGE('',*,*,#101,.F.);
#806=DIRECTION('',(0.,-1.,0.));
#807=VECTOR('',#806,1.);
#808=CARTESIAN_POINT('',(28.,-0.5,-13.2));
#809=LINE('',#808,#807);
#810=EDGE_CURVE('E356',#91,#550,#809,.T.);
#811=ORIENTED_EDGE('',*,*,#810,.T.);
#812=EDGE_LOOP('',(#803,#804,#805,#811));
#813=FACE_BOUND('',#812,.T.);
#814=ADVANCED_FACE('F570',(#813),#802,.F.);
#815=CARTESIAN_POINT('',(-28.,-0.5,-13.2));
#816=DIRECTION('',(0.,0.,-1.));
#817=DIRECTION('',(-1.,0.,0.));
#818=AXIS2_PLACEMENT_3D('',#815,#816,#817);
#819=PLANE('',#818);
#820=ORIENTED_EDGE('',*,*,#559,.T.);
#821=ORIENTED_EDGE('',*,*,#810,.F.);
#822=ORIENTED_EDGE('',*,*,#92,.F.);
#823=DIRECTION('',(0.,-1.,0.));
#824=VECTOR('',#823,1.);
#825=CARTESIAN_POINT('',(-28.,-0.5,-13.2));
#826=LINE('',#825,#824);
#827=EDGE_CURVE('E358',#83,#558,#826,.T.);
#828=ORIENTED_EDGE('',*,*,#827,.T.);
#829=EDGE_LOOP('',(#820,#821,#822,#828));
#830=FACE_BOUND('',#829,.T.);
#831=ADVANCED_FACE('F574',(#830),#819,.F.);
#832=CARTESIAN_POINT('',(-28.,-0.5,-13.));
#833=DIRECTION('',(0.,-1.,0.));
#834=DIRECTION('',(0.,0.,-1.));
#835=AXIS2_PLACEMENT_3D('',#832,#833,#834);
#836=CYLINDRICAL_SURFACE('',#835,0.2);
#837=ORIENTED_EDGE('',*,*,#566,.T.);
#838=ORIENTED_EDGE('',*,*,#827,.F.);
#839=ORIENTED_EDGE('',*,*,#84,.F.);
#840=DIRECTION('',(0.,-1.,0.));
#841=VECTOR('',#840,1.);
#842=CARTESIAN_POINT('',(-28.2,-0.5,-13.));
#843=LINE('',#842,#841);
#844=EDGE_CURVE('E360',#74,#507,#843,.T.);
#845=ORIENTED_EDGE('',*,*,#844,.T.);
#846=EDGE_LOOP('',(#837,#838,#839,#845));
#847=FACE_BOUND('',#846,.T.);
#848=ADVANCED_FACE('F578',(#847),#836,.F.);
#849=CARTESIAN_POINT('',(-28.2,-0.5,13.));
#850=DIRECTION('',(-1.,0.,0.));
#851=DIRECTION('',(0.,0.,1.));
#852=AXIS2_PLACEMENT_3D('',#849,#850,#851);
#853=PLANE('',#852);
#854=ORIENTED_EDGE('',*,*,#508,.T.);
#855=ORIENTED_EDGE('',*,*,#844,.F.);
#856=ORIENTED_EDGE('',*,*,#75,.F.);
#857=ORIENTED_EDGE('',*,*,#735,.T.);
#858=EDGE_LOOP('',(#854,#855,#856,#857));
#859=FACE_BOUND('',#858,.T.);
#860=ADVANCED_FACE('F582',(#859),#853,.F.);
#861=CARTESIAN_POINT('',(-16.65,-0.5,2.45));
#862=DIRECTION('',(-0.999945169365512,-0.0104717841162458,0.));
#863=DIRECTION('',(0.0104717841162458,-0.999945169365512,0.));
#864=AXIS2_PLACEMENT_3D('',#861,#862,#863);
#865=PLANE('',#864);
#866=DIRECTION('',(-0.0104712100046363,0.999890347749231,-0.0104712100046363));
#867=VECTOR('',#866,1.);
#868=CARTESIAN_POINT('',(-16.65,-0.5,-2.45));
#869=LINE('',#868,#867);
#870=CARTESIAN_POINT('',(-16.574511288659,-7.70837742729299,-2.37451128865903));
#871=VERTEX_POINT('',#870);
#872=EDGE_CURVE('E292',#871,#29,#869,.T.);
#873=ORIENTED_EDGE('',*,*,#872,.F.);
#874=DIRECTION('',(0.,0.,-1.));
#875=VECTOR('',#874,1.);
#876=CARTESIAN_POINT('',(-16.574511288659,-7.708377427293,2.36622113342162));
#877=LINE('',#876,#875);
#878=CARTESIAN_POINT('',(-16.574511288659,-7.70837742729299,2.37451128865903));
#879=VERTEX_POINT('',#878);
#880=EDGE_CURVE('E11',#871,#879,#877,.F.);
#881=ORIENTED_EDGE('',*,*,#880,.T.);
#882=DIRECTION('',(-0.0104712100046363,0.999890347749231,0.0104712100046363));
#883=VECTOR('',#882,1.);
#884=CARTESIAN_POINT('',(-16.65,-0.5,2.45));
#885=LINE('',#884,#883);
#886=EDGE_CURVE('E291',#879,#39,#885,.T.);
#887=ORIENTED_EDGE('',*,*,#886,.T.);
#888=ORIENTED_EDGE('',*,*,#40,.T.);
#889=EDGE_LOOP('',(#873,#881,#887,#888));
#890=FACE_BOUND('',#889,.T.);
#891=ADVANCED_FACE('F520',(#890),#865,.T.);
#892=CARTESIAN_POINT('',(-16.65,-0.5,-2.45));
#893=DIRECTION('',(0.,-0.0104717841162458,-0.999945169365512));
#894=DIRECTION('',(0.,0.999945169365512,-0.0104717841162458));
#895=AXIS2_PLACEMENT_3D('',#892,#893,#894);
#896=PLANE('',#895);
#897=DIRECTION('',(0.0104712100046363,0.999890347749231,-0.0104712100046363));
#898=VECTOR('',#897,1.);
#899=CARTESIAN_POINT('',(-13.3505372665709,-0.551303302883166,-2.44946273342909));
#900=LINE('',#899,#898);
#901=CARTESIAN_POINT('',(-13.425488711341,-7.708377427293,-2.37451128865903));
#902=VERTEX_POINT('',#901);
#903=EDGE_CURVE('E295',#902,#31,#900,.T.);
#904=ORIENTED_EDGE('',*,*,#903,.F.);
#905=DIRECTION('',(1.,0.,0.));
#906=VECTOR('',#905,1.);
#907=CARTESIAN_POINT('',(-16.5662211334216,-7.708377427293,-2.37451128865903));
#908=LINE('',#907,#906);
#909=EDGE_CURVE('E44',#902,#871,#908,.F.);
#910=ORIENTED_EDGE('',*,*,#909,.T.);
#911=ORIENTED_EDGE('',*,*,#872,.T.);
#912=ORIENTED_EDGE('',*,*,#32,.T.);
#913=EDGE_LOOP('',(#904,#910,#911,#912));
#914=FACE_BOUND('',#913,.T.);
#915=ADVANCED_FACE('F556',(#914),#896,.T.);
#916=CARTESIAN_POINT('',(-13.35,-0.5,2.45));
#917=DIRECTION('',(0.999945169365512,-0.0104717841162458,0.));
#918=DIRECTION('',(0.0104717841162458,0.999945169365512,0.));
#919=AXIS2_PLACEMENT_3D('',#916,#917,#918);
#920=PLANE('',#919);
#921=DIRECTION('',(0.0104712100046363,0.999890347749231,0.0104712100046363));
#922=VECTOR('',#921,1.);
#923=CARTESIAN_POINT('',(-13.3503618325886,-0.53455120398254,2.44963816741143));
#924=LINE('',#923,#922);
#925=CARTESIAN_POINT('',(-13.425488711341,-7.70837742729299,2.37451128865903));
#926=VERTEX_POINT('',#925);
#927=EDGE_CURVE('E297',#926,#47,#924,.T.);
#928=ORIENTED_EDGE('',*,*,#927,.F.);
#929=DIRECTION('',(0.,0.,1.));
#930=VECTOR('',#929,1.);
#931=CARTESIAN_POINT('',(-13.425488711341,-7.708377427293,-2.36622113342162));
#932=LINE('',#931,#930);
#933=EDGE_CURVE('E59',#926,#902,#932,.F.);
#934=ORIENTED_EDGE('',*,*,#933,.T.);
#935=ORIENTED_EDGE('',*,*,#903,.T.);
#936=ORIENTED_EDGE('',*,*,#54,.T.);
#937=EDGE_LOOP('',(#928,#934,#935,#936));
#938=FACE_BOUND('',#937,.T.);
#939=ADVANCED_FACE('F538',(#938),#920,.T.);
#940=CARTESIAN_POINT('',(-16.65,-0.5,2.45));
#941=DIRECTION('',(0.,-0.0104717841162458,0.999945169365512));
#942=DIRECTION('',(0.,-0.999945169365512,-0.0104717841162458));
#943=AXIS2_PLACEMENT_3D('',#940,#941,#942);
#944=PLANE('',#943);
#945=ORIENTED_EDGE('',*,*,#886,.F.);
#946=DIRECTION('',(-1.,0.,0.));
#947=VECTOR('',#946,1.);
#948=CARTESIAN_POINT('',(-13.4337788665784,-7.708377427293,2.37451128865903));
#949=LINE('',#948,#947);
#950=EDGE_CURVE('E485',#879,#926,#949,.F.);
#951=ORIENTED_EDGE('',*,*,#950,.T.);
#952=ORIENTED_EDGE('',*,*,#927,.T.);
#953=ORIENTED_EDGE('',*,*,#48,.T.);
#954=EDGE_LOOP('',(#945,#951,#952,#953));
#955=FACE_BOUND('',#954,.T.);
#956=ADVANCED_FACE('F523',(#955),#944,.T.);
#957=CARTESIAN_POINT('',(-16.65,-8.5,-2.45));
#958=DIRECTION('',(0.,-1.,0.));
#959=DIRECTION('',(0.,0.,-1.));
#960=AXIS2_PLACEMENT_3D('',#957,#958,#959);
#961=PLANE('',#960);
#962=DIRECTION('',(0.,0.,-1.));
#963=VECTOR('',#962,1.);
#964=CARTESIAN_POINT('',(-14.2254448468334,-8.5,2.36622113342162));
#965=LINE('',#964,#963);
#966=CARTESIAN_POINT('',(-14.2254448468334,-8.5,-1.57455515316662));
#967=VERTEX_POINT('',#966);
#968=CARTESIAN_POINT('',(-14.2254448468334,-8.5,1.57455515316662));
#969=VERTEX_POINT('',#968);
#970=EDGE_CURVE('E480',#967,#969,#965,.F.);
#971=ORIENTED_EDGE('',*,*,#970,.T.);
#972=DIRECTION('',(1.,0.,0.));
#973=VECTOR('',#972,1.);
#974=CARTESIAN_POINT('',(-16.5662211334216,-8.5,1.57455515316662));
#975=LINE('',#974,#973);
#976=CARTESIAN_POINT('',(-15.7745551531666,-8.5,1.57455515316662));
#977=VERTEX_POINT('',#976);
#978=EDGE_CURVE('E482',#969,#977,#975,.F.);
#979=ORIENTED_EDGE('',*,*,#978,.T.);
#980=DIRECTION('',(0.,0.,1.));
#981=VECTOR('',#980,1.);
#982=CARTESIAN_POINT('',(-15.7745551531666,-8.5,-2.36622113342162));
#983=LINE('',#982,#981);
#984=CARTESIAN_POINT('',(-15.7745551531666,-8.5,-1.57455515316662));
#985=VERTEX_POINT('',#984);
#986=EDGE_CURVE('E476',#977,#985,#983,.F.);
#987=ORIENTED_EDGE('',*,*,#986,.T.);
#988=DIRECTION('',(-1.,0.,0.));
#989=VECTOR('',#988,1.);
#990=CARTESIAN_POINT('',(-13.4337788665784,-8.5,-1.57455515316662));
#991=LINE('',#990,#989);
#992=EDGE_CURVE('E478',#985,#967,#991,.F.);
#993=ORIENTED_EDGE('',*,*,#992,.T.);
#994=EDGE_LOOP('',(#971,#979,#987,#993));
#995=FACE_BOUND('',#994,.T.);
#996=ADVANCED_FACE('F530',(#995),#961,.T.);
#997=CARTESIAN_POINT('',(13.35,-0.5,-2.45));
#998=DIRECTION('',(-0.999945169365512,-0.0104717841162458,0.));
#999=DIRECTION('',(0.0104717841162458,-0.999945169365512,0.));
#1000=AXIS2_PLACEMENT_3D('',#997,#998,#999);
#1001=PLANE('',#1000);
#1002=DIRECTION('',(-0.0104712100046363,0.999890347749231,-0.0104712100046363));
#1003=VECTOR('',#1002,1.);
#1004=CARTESIAN_POINT('',(13.35,-0.5,-2.45));
#1005=LINE('',#1004,#1003);
#1006=CARTESIAN_POINT('',(13.425488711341,-7.70837742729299,-2.37451128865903));
#1007=VERTEX_POINT('',#1006);
#1008=EDGE_CURVE('E245',#1007,#133,#1005,.T.);
#1009=ORIENTED_EDGE('',*,*,#1008,.F.);
#1010=DIRECTION('',(0.,0.,-1.));
#1011=VECTOR('',#1010,1.);
#1012=CARTESIAN_POINT('',(13.425488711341,-7.708377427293,-2.45));
#1013=LINE('',#1012,#1011);
#1014=CARTESIAN_POINT('',(13.425488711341,-7.708377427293,2.37451128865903));
#1015=VERTEX_POINT('',#1014);
#1016=EDGE_CURVE('E474',#1007,#1015,#1013,.F.);
#1017=ORIENTED_EDGE('',*,*,#1016,.T.);
#1018=DIRECTION('',(-0.0104712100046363,0.999890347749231,0.0104712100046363));
#1019=VECTOR('',#1018,1.);
#1020=CARTESIAN_POINT('',(13.3505372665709,-0.551303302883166,2.44946273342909));
#1021=LINE('',#1020,#1019);
#1022=EDGE_CURVE('E263',#1015,#143,#1021,.T.);
#1023=ORIENTED_EDGE('',*,*,#1022,.T.);
#1024=ORIENTED_EDGE('',*,*,#144,.T.);
#1025=EDGE_LOOP('',(#1009,#1017,#1023,#1024));
#1026=FACE_BOUND('',#1025,.T.);
#1027=ADVANCED_FACE('F261',(#1026),#1001,.T.);
#1028=CARTESIAN_POINT('',(13.35,-0.5,-2.45));
#1029=DIRECTION('',(0.,-0.0104717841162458,-0.999945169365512));
#1030=DIRECTION('',(0.,0.999945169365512,-0.0104717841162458));
#1031=AXIS2_PLACEMENT_3D('',#1028,#1029,#1030);
#1032=PLANE('',#1031);
#1033=DIRECTION('',(0.0104712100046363,0.999890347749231,-0.0104712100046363));
#1034=VECTOR('',#1033,1.);
#1035=CARTESIAN_POINT('',(16.65,-0.5,-2.45));
#1036=LINE('',#1035,#1034);
#1037=CARTESIAN_POINT('',(16.574511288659,-7.70837742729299,-2.37451128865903));
#1038=VERTEX_POINT('',#1037);
#1039=EDGE_CURVE('E257',#1038,#135,#1036,.T.);
#1040=ORIENTED_EDGE('',*,*,#1039,.F.);
#1041=DIRECTION('',(1.,0.,0.));
#1042=VECTOR('',#1041,1.);
#1043=CARTESIAN_POINT('',(13.35,-7.708377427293,-2.37451128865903));
#1044=LINE('',#1043,#1042);
#1045=EDGE_CURVE('E253',#1038,#1007,#1044,.F.);
#1046=ORIENTED_EDGE('',*,*,#1045,.T.);
#1047=ORIENTED_EDGE('',*,*,#1008,.T.);
#1048=ORIENTED_EDGE('',*,*,#136,.T.);
#1049=EDGE_LOOP('',(#1040,#1046,#1047,#1048));
#1050=FACE_BOUND('',#1049,.T.);
#1051=ADVANCED_FACE('F248',(#1050),#1032,.T.);
#1052=CARTESIAN_POINT('',(16.65,-0.5,-2.45));
#1053=DIRECTION('',(0.999945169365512,-0.0104717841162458,0.));
#1054=DIRECTION('',(0.0104717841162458,0.999945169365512,0.));
#1055=AXIS2_PLACEMENT_3D('',#1052,#1053,#1054);
#1056=PLANE('',#1055);
#1057=DIRECTION('',(0.0104712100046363,0.999890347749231,0.0104712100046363));
#1058=VECTOR('',#1057,1.);
#1059=CARTESIAN_POINT('',(16.6496381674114,-0.53455120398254,2.44963816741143));
#1060=LINE('',#1059,#1058);
#1061=CARTESIAN_POINT('',(16.574511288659,-7.70837742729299,2.37451128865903));
#1062=VERTEX_POINT('',#1061);
#1063=EDGE_CURVE('E277',#1062,#151,#1060,.T.);
#1064=ORIENTED_EDGE('',*,*,#1063,.F.);
#1065=DIRECTION('',(0.,0.,1.));
#1066=VECTOR('',#1065,1.);
#1067=CARTESIAN_POINT('',(16.574511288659,-7.708377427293,-2.45));
#1068=LINE('',#1067,#1066);
#1069=EDGE_CURVE('E471',#1062,#1038,#1068,.F.);
#1070=ORIENTED_EDGE('',*,*,#1069,.T.);
#1071=ORIENTED_EDGE('',*,*,#1039,.T.);
#1072=ORIENTED_EDGE('',*,*,#158,.T.);
#1073=EDGE_LOOP('',(#1064,#1070,#1071,#1072));
#1074=FACE_BOUND('',#1073,.T.);
#1075=ADVANCED_FACE('F713',(#1074),#1056,.T.);
#1076=CARTESIAN_POINT('',(13.35,-0.5,2.45));
#1077=DIRECTION('',(0.,-0.0104717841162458,0.999945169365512));
#1078=DIRECTION('',(0.,-0.999945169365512,-0.0104717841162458));
#1079=AXIS2_PLACEMENT_3D('',#1076,#1077,#1078);
#1080=PLANE('',#1079);
#1081=ORIENTED_EDGE('',*,*,#1022,.F.);
#1082=DIRECTION('',(-1.,0.,0.));
#1083=VECTOR('',#1082,1.);
#1084=CARTESIAN_POINT('',(13.35,-7.708377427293,2.37451128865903));
#1085=LINE('',#1084,#1083);
#1086=EDGE_CURVE('E468',#1015,#1062,#1085,.F.);
#1087=ORIENTED_EDGE('',*,*,#1086,.T.);
#1088=ORIENTED_EDGE('',*,*,#1063,.T.);
#1089=ORIENTED_EDGE('',*,*,#152,.T.);
#1090=EDGE_LOOP('',(#1081,#1087,#1088,#1089));
#1091=FACE_BOUND('',#1090,.T.);
#1092=ADVANCED_FACE('F705',(#1091),#1080,.T.);
#1093=CARTESIAN_POINT('',(13.35,-8.5,2.45));
#1094=DIRECTION('',(0.,1.,0.));
#1095=DIRECTION('',(0.,0.,1.));
#1096=AXIS2_PLACEMENT_3D('',#1093,#1094,#1095);
#1097=PLANE('',#1096);
#1098=DIRECTION('',(0.,0.,-1.));
#1099=VECTOR('',#1098,1.);
#1100=CARTESIAN_POINT('',(15.7745551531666,-8.5,2.45));
#1101=LINE('',#1100,#1099);
#1102=CARTESIAN_POINT('',(15.7745551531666,-8.5,-1.57455515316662));
#1103=VERTEX_POINT('',#1102);
#1104=CARTESIAN_POINT('',(15.7745551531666,-8.5,1.57455515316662));
#1105=VERTEX_POINT('',#1104);
#1106=EDGE_CURVE('E463',#1103,#1105,#1101,.F.);
#1107=ORIENTED_EDGE('',*,*,#1106,.T.);
#1108=DIRECTION('',(1.,0.,0.));
#1109=VECTOR('',#1108,1.);
#1110=CARTESIAN_POINT('',(13.35,-8.5,1.57455515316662));
#1111=LINE('',#1110,#1109);
#1112=CARTESIAN_POINT('',(14.2254448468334,-8.5,1.57455515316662));
#1113=VERTEX_POINT('',#1112);
#1114=EDGE_CURVE('E465',#1105,#1113,#1111,.F.);
#1115=ORIENTED_EDGE('',*,*,#1114,.T.);
#1116=DIRECTION('',(0.,0.,1.));
#1117=VECTOR('',#1116,1.);
#1118=CARTESIAN_POINT('',(14.2254448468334,-8.5,2.45));
#1119=LINE('',#1118,#1117);
#1120=CARTESIAN_POINT('',(14.2254448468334,-8.5,-1.57455515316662));
#1121=VERTEX_POINT('',#1120);
#1122=EDGE_CURVE('E439',#1113,#1121,#1119,.F.);
#1123=ORIENTED_EDGE('',*,*,#1122,.T.);
#1124=DIRECTION('',(-1.,0.,0.));
#1125=VECTOR('',#1124,1.);
#1126=CARTESIAN_POINT('',(13.35,-8.5,-1.57455515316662));
#1127=LINE('',#1126,#1125);
#1128=EDGE_CURVE('E461',#1121,#1103,#1127,.F.);
#1129=ORIENTED_EDGE('',*,*,#1128,.T.);
#1130=EDGE_LOOP('',(#1107,#1115,#1123,#1129));
#1131=FACE_BOUND('',#1130,.T.);
#1132=ADVANCED_FACE('F672',(#1131),#1097,.F.);
#1133=CARTESIAN_POINT('',(13.35,-7.7,-1.57455515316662));
#1134=DIRECTION('',(-1.,0.,0.));
#1135=DIRECTION('',(0.,0.,1.));
#1136=AXIS2_PLACEMENT_3D('',#1133,#1134,#1135);
#1137=CYLINDRICAL_SURFACE('',#1136,0.8);
#1138=CARTESIAN_POINT('',(14.2254448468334,-7.7,-1.57455515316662));
#1139=DIRECTION('',(-0.707106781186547,0.,0.707106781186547));
#1140=DIRECTION('',(0.707106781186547,0.,0.707106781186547));
#1141=AXIS2_PLACEMENT_3D('',#1138,#1139,#1140);
#1142=ELLIPSE('',#1141,1.13137084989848,0.8);
#1143=EDGE_CURVE('E494',#1007,#1121,#1142,.T.);
#1144=ORIENTED_EDGE('',*,*,#1143,.F.);
#1145=ORIENTED_EDGE('',*,*,#1045,.F.);
#1146=CARTESIAN_POINT('',(15.7745551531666,-7.7,-1.57455515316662));
#1147=DIRECTION('',(-0.707106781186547,0.,-0.707106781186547));
#1148=DIRECTION('',(-0.707106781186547,0.,0.707106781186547));
#1149=AXIS2_PLACEMENT_3D('',#1146,#1147,#1148);
#1150=ELLIPSE('',#1149,1.13137084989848,0.8);
#1151=EDGE_CURVE('E267',#1103,#1038,#1150,.F.);
#1152=ORIENTED_EDGE('',*,*,#1151,.F.);
#1153=ORIENTED_EDGE('',*,*,#1128,.F.);
#1154=EDGE_LOOP('',(#1144,#1145,#1152,#1153));
#1155=FACE_BOUND('',#1154,.T.);
#1156=ADVANCED_FACE('F668',(#1155),#1137,.T.);
#1157=CARTESIAN_POINT('',(15.7745551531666,-7.7,2.45));
#1158=DIRECTION('',(0.,0.,-1.));
#1159=DIRECTION('',(-1.,0.,0.));
#1160=AXIS2_PLACEMENT_3D('',#1157,#1158,#1159);
#1161=CYLINDRICAL_SURFACE('',#1160,0.8);
#1162=ORIENTED_EDGE('',*,*,#1151,.T.);
#1163=ORIENTED_EDGE('',*,*,#1069,.F.);
#1164=CARTESIAN_POINT('',(15.7745551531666,-7.7,1.57455515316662));
#1165=DIRECTION('',(0.707106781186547,0.,-0.707106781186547));
#1166=DIRECTION('',(-0.707106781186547,0.,-0.707106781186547));
#1167=AXIS2_PLACEMENT_3D('',#1164,#1165,#1166);
#1168=ELLIPSE('',#1167,1.13137084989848,0.8);
#1169=EDGE_CURVE('E492',#1105,#1062,#1168,.F.);
#1170=ORIENTED_EDGE('',*,*,#1169,.F.);
#1171=ORIENTED_EDGE('',*,*,#1106,.F.);
#1172=EDGE_LOOP('',(#1162,#1163,#1170,#1171));
#1173=FACE_BOUND('',#1172,.T.);
#1174=ADVANCED_FACE('F664',(#1173),#1161,.T.);
#1175=CARTESIAN_POINT('',(14.2254448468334,-7.7,2.45));
#1176=DIRECTION('',(0.,0.,1.));
#1177=DIRECTION('',(1.,0.,0.));
#1178=AXIS2_PLACEMENT_3D('',#1175,#1176,#1177);
#1179=CYLINDRICAL_SURFACE('',#1178,0.8);
#1180=ORIENTED_EDGE('',*,*,#1143,.T.);
#1181=ORIENTED_EDGE('',*,*,#1122,.F.);
#1182=CARTESIAN_POINT('',(14.2254448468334,-7.7,1.57455515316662));
#1183=DIRECTION('',(0.707106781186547,0.,0.707106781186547));
#1184=DIRECTION('',(-0.707106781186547,0.,0.707106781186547));
#1185=AXIS2_PLACEMENT_3D('',#1182,#1183,#1184);
#1186=ELLIPSE('',#1185,1.13137084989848,0.8);
#1187=EDGE_CURVE('E490',#1015,#1113,#1186,.T.);
#1188=ORIENTED_EDGE('',*,*,#1187,.F.);
#1189=ORIENTED_EDGE('',*,*,#1016,.F.);
#1190=EDGE_LOOP('',(#1180,#1181,#1188,#1189));
#1191=FACE_BOUND('',#1190,.T.);
#1192=ADVANCED_FACE('F660',(#1191),#1179,.T.);
#1193=CARTESIAN_POINT('',(13.35,-7.7,1.57455515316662));
#1194=DIRECTION('',(1.,0.,0.));
#1195=DIRECTION('',(0.,0.,-1.));
#1196=AXIS2_PLACEMENT_3D('',#1193,#1194,#1195);
#1197=CYLINDRICAL_SURFACE('',#1196,0.8);
#1198=ORIENTED_EDGE('',*,*,#1169,.T.);
#1199=ORIENTED_EDGE('',*,*,#1086,.F.);
#1200=ORIENTED_EDGE('',*,*,#1187,.T.);
#1201=ORIENTED_EDGE('',*,*,#1114,.F.);
#1202=EDGE_LOOP('',(#1198,#1199,#1200,#1201));
#1203=FACE_BOUND('',#1202,.T.);
#1204=ADVANCED_FACE('F657',(#1203),#1197,.T.);
#1205=CARTESIAN_POINT('',(-16.65,-7.7,-1.57455515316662));
#1206=DIRECTION('',(1.,0.,0.));
#1207=DIRECTION('',(0.,0.,-1.));
#1208=AXIS2_PLACEMENT_3D('',#1205,#1206,#1207);
#1209=CYLINDRICAL_SURFACE('',#1208,0.8);
#1210=CARTESIAN_POINT('',(-15.7745551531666,-7.7,-1.57455515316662));
#1211=DIRECTION('',(0.707106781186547,0.,-0.707106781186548));
#1212=DIRECTION('',(-0.707106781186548,0.,-0.707106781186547));
#1213=AXIS2_PLACEMENT_3D('',#1210,#1211,#1212);
#1214=ELLIPSE('',#1213,1.13137084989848,0.8);
#1215=EDGE_CURVE('E502',#871,#985,#1214,.F.);
#1216=ORIENTED_EDGE('',*,*,#1215,.F.);
#1217=ORIENTED_EDGE('',*,*,#909,.F.);
#1218=CARTESIAN_POINT('',(-14.2254448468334,-7.7,-1.57455515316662));
#1219=DIRECTION('',(0.707106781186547,0.,0.707106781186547));
#1220=DIRECTION('',(0.707106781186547,0.,-0.707106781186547));
#1221=AXIS2_PLACEMENT_3D('',#1218,#1219,#1220);
#1222=ELLIPSE('',#1221,1.13137084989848,0.8);
#1223=EDGE_CURVE('E39',#967,#902,#1222,.T.);
#1224=ORIENTED_EDGE('',*,*,#1223,.F.);
#1225=ORIENTED_EDGE('',*,*,#992,.F.);
#1226=EDGE_LOOP('',(#1216,#1217,#1224,#1225));
#1227=FACE_BOUND('',#1226,.T.);
#1228=ADVANCED_FACE('F37',(#1227),#1209,.T.);
#1229=CARTESIAN_POINT('',(-14.2254448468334,-7.7,-2.45));
#1230=DIRECTION('',(0.,0.,1.));
#1231=DIRECTION('',(1.,0.,0.));
#1232=AXIS2_PLACEMENT_3D('',#1229,#1230,#1231);
#1233=CYLINDRICAL_SURFACE('',#1232,0.8);
#1234=ORIENTED_EDGE('',*,*,#1223,.T.);
#1235=ORIENTED_EDGE('',*,*,#933,.F.);
#1236=CARTESIAN_POINT('',(-14.2254448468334,-7.7,1.57455515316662));
#1237=DIRECTION('',(-0.707106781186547,0.,0.707106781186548));
#1238=DIRECTION('',(0.707106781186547,0.,0.707106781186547));
#1239=AXIS2_PLACEMENT_3D('',#1236,#1237,#1238);
#1240=ELLIPSE('',#1239,1.13137084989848,0.8);
#1241=EDGE_CURVE('E501',#969,#926,#1240,.T.);
#1242=ORIENTED_EDGE('',*,*,#1241,.F.);
#1243=ORIENTED_EDGE('',*,*,#970,.F.);
#1244=EDGE_LOOP('',(#1234,#1235,#1242,#1243));
#1245=FACE_BOUND('',#1244,.T.);
#1246=ADVANCED_FACE('F512',(#1245),#1233,.T.);
#1247=CARTESIAN_POINT('',(-15.7745551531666,-7.7,-2.45));
#1248=DIRECTION('',(0.,0.,-1.));
#1249=DIRECTION('',(-1.,0.,0.));
#1250=AXIS2_PLACEMENT_3D('',#1247,#1248,#1249);
#1251=CYLINDRICAL_SURFACE('',#1250,0.8);
#1252=ORIENTED_EDGE('',*,*,#1215,.T.);
#1253=ORIENTED_EDGE('',*,*,#986,.F.);
#1254=CARTESIAN_POINT('',(-15.7745551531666,-7.7,1.57455515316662));
#1255=DIRECTION('',(-0.707106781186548,0.,-0.707106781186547));
#1256=DIRECTION('',(0.707106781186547,0.,-0.707106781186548));
#1257=AXIS2_PLACEMENT_3D('',#1254,#1255,#1256);
#1258=ELLIPSE('',#1257,1.13137084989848,0.8);
#1259=EDGE_CURVE('E499',#879,#977,#1258,.F.);
#1260=ORIENTED_EDGE('',*,*,#1259,.F.);
#1261=ORIENTED_EDGE('',*,*,#880,.F.);
#1262=EDGE_LOOP('',(#1252,#1253,#1260,#1261));
#1263=FACE_BOUND('',#1262,.T.);
#1264=ADVANCED_FACE('F517',(#1263),#1251,.T.);
#1265=CARTESIAN_POINT('',(-16.65,-7.7,1.57455515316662));
#1266=DIRECTION('',(-1.,0.,0.));
#1267=DIRECTION('',(0.,0.,1.));
#1268=AXIS2_PLACEMENT_3D('',#1265,#1266,#1267);
#1269=CYLINDRICAL_SURFACE('',#1268,0.8);
#1270=ORIENTED_EDGE('',*,*,#1241,.T.);
#1271=ORIENTED_EDGE('',*,*,#950,.F.);
#1272=ORIENTED_EDGE('',*,*,#1259,.T.);
#1273=ORIENTED_EDGE('',*,*,#978,.F.);
#1274=EDGE_LOOP('',(#1270,#1271,#1272,#1273));
#1275=FACE_BOUND('',#1274,.T.);
#1276=ADVANCED_FACE('F527',(#1275),#1269,.T.);
#1277=CLOSED_SHELL('',(#162,#204,#235,#268,#299,#332,#363,#396,#418,#494,#580,#604,#622,#640,
#658,#676,#694,#712,#724,#746,#763,#780,#797,#814,#831,#848,#860,#891,#915,#939,#956,#996,#1027,
#1051,#1075,#1092,#1132,#1156,#1174,#1192,#1204,#1228,#1246,#1264,#1276));
#1278=MANIFOLD_SOLID_BREP('B2',#1277);
#1279=ADVANCED_BREP_SHAPE_REPRESENTATION('',(#18,#1278),#14);
#1280=SHAPE_DEFINITION_REPRESENTATION(#9,#1279);
ENDSEC;
END-ISO-10303-21;
